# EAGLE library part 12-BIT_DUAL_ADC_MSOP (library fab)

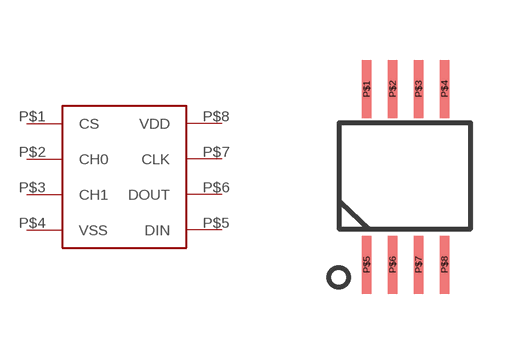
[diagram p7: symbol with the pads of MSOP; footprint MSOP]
Designator prefix -

## 12-BIT_DUAL_ADC_MSOP  [MSOP]
P$1  CS
P$2  CH0
P$3  CH1
P$4  VSS
P$5  DIN
P$6  DOUT
P$7  CLK
P$8  VDD

## Footprint MSOP (pad centres in mm)
smd 0.24 x 1.45: P$1 -0.65,2.45; P$2 0,2.45; P$3 0.65,2.45; P$4 1.3,2.45; P$5 -0.65,-1.95; P$6 0,-1.95; P$7 0.65,-1.95; P$8 1.3,-1.95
